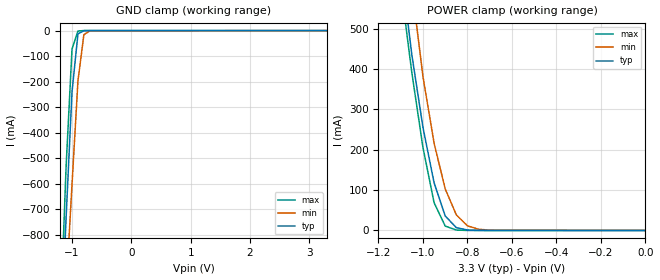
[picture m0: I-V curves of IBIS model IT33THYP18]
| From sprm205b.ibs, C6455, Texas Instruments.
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|   Model IT33THYP18
[Model]   IT33THYP18
Model_type   Input
Polarity   Non-Inverting
Vinl =   0.8000V
Vinh =   2.0000V
C_comp   0.4880pF   0.4420pF   0.5340pF
[Temperature Range]   25.0000   0.1250k   -40.0000
[Pullup Reference]   3.3000V   3.0000V   3.6000V
[Pulldown Reference]   0.000V   0.000V   0.000V
[POWER Clamp Reference]   3.3000V   3.0000V   3.6000V
[GND Clamp Reference]   0.000V   0.000V   0.000V
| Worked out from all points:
|   GND clamp passes 1 mA (typ) near -0.80 V on its own axis
|   POWER clamp passes 1 mA (typ) near -0.79 V on its own axis
[GND_clamp]
| voltage   I(typ)   I(min)   I(max)
-3.3V     -15.87A    -14.33A    -17.08A
-1.2V     -1.258A    -1.449A    -1.156A
-1.1V     -733.9mA   -1.017A    -533.5mA
-1V       -239.8mA   -601.8mA   -72.14mA
-900mV    -13.06mA   -197.1mA   -1.578mA
-800mV    -373.9uA   -15.94mA   -15.57uA
-700mV    -8.212uA   -1.068mA   -3.557uA
3.3V      95.07nA    98.03nA    329.8nA
[POWER_clamp]
| voltage   I(typ)   I(min)   I(max)
-3.3V     13.82A     12.46A     14.94A
-1.1V     659.5mA    849.4mA    605mA
-1.05V    434.5mA    602.9mA    390.3mA
-1V       254.9mA    380.7mA    204.9mA
-950mV    117.9mA    215.7mA    68.66mA
-900mV    35.85mA    102.9mA    10.85mA
-850mV    7.018mA    38.47mA    1.067mA
-800mV    1.123mA    11.47mA    96.7uA
-750mV    171.4uA    3.055mA    9.143uA
-700mV    26.15uA    783uA      1.258uA
0V        95.07nA    65.48nA    353.6nA
